VERSION 5.8 ;
BUSBITCHARS "[]" ;
DIVIDERCHAR "/" ;
UNITS
    DATABASE MICRONS 1000 ;
END UNITS

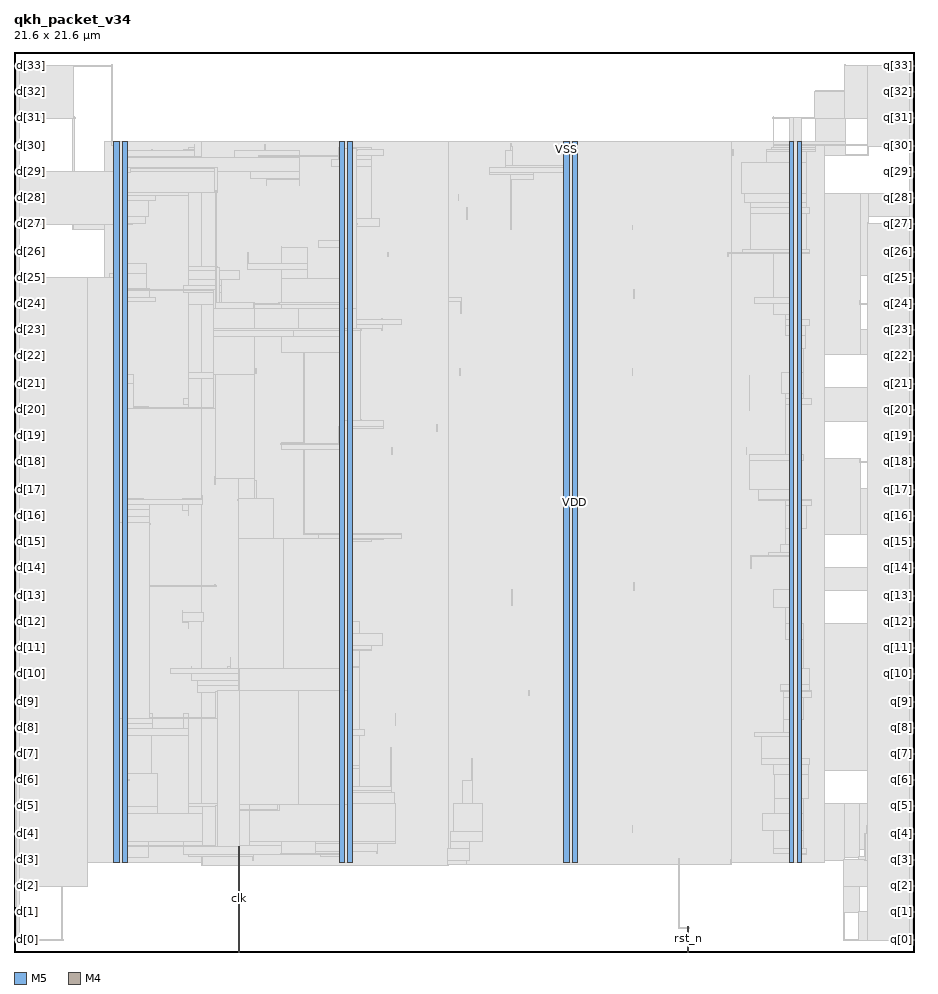
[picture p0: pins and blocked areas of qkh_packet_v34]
MACRO qkh_packet_v34
  FOREIGN qkh_packet_v34 0 0 ;
  CLASS BLOCK ;
  SIZE 21.6 BY 21.6 ;
  PIN clk
    DIRECTION INPUT ;
    USE SIGNAL ;
    PORT
      LAYER M5 ;
        RECT  5.376 0 5.4 0.084 ;
    END
    PORT
      LAYER M5 ;
        RECT  5.376 0.016 5.4 2.533 ;
    END
  END clk
  PIN d[0]
    DIRECTION INPUT ;
    USE SIGNAL ;
    PORT
      LAYER M4 ;
        RECT  0 0.288 0.084 0.312 ;
    END
  END d[0]
  PIN d[10]
    DIRECTION INPUT ;
    USE SIGNAL ;
    PORT
      LAYER M4 ;
        RECT  0 6.672 0.084 6.696 ;
    END
  END d[10]
  PIN d[11]
    DIRECTION INPUT ;
    USE SIGNAL ;
    PORT
      LAYER M4 ;
        RECT  0 7.296 0.084 7.32 ;
    END
  END d[11]
  PIN d[12]
    DIRECTION INPUT ;
    USE SIGNAL ;
    PORT
      LAYER M4 ;
        RECT  0 7.92 0.084 7.944 ;
    END
  END d[12]
  PIN d[13]
    DIRECTION INPUT ;
    USE SIGNAL ;
    PORT
      LAYER M4 ;
        RECT  0 8.544 0.084 8.568 ;
    END
  END d[13]
  PIN d[14]
    DIRECTION INPUT ;
    USE SIGNAL ;
    PORT
      LAYER M4 ;
        RECT  0 9.216 0.084 9.24 ;
    END
  END d[14]
  PIN d[15]
    DIRECTION INPUT ;
    USE SIGNAL ;
    PORT
      LAYER M4 ;
        RECT  0 9.84 0.084 9.864 ;
    END
  END d[15]
  PIN d[16]
    DIRECTION INPUT ;
    USE SIGNAL ;
    PORT
      LAYER M4 ;
        RECT  0 10.464 0.084 10.488 ;
    END
  END d[16]
  PIN d[17]
    DIRECTION INPUT ;
    USE SIGNAL ;
    PORT
      LAYER M4 ;
        RECT  0 11.088 0.084 11.112 ;
    END
  END d[17]
  PIN d[18]
    DIRECTION INPUT ;
    USE SIGNAL ;
    PORT
      LAYER M4 ;
        RECT  0 11.76 0.084 11.784 ;
    END
  END d[18]
  PIN d[19]
    DIRECTION INPUT ;
    USE SIGNAL ;
    PORT
      LAYER M4 ;
        RECT  0 12.384 0.084 12.408 ;
    END
  END d[19]
  PIN d[1]
    DIRECTION INPUT ;
    USE SIGNAL ;
    PORT
      LAYER M4 ;
        RECT  0 0.96 0.084 0.984 ;
    END
  END d[1]
  PIN d[20]
    DIRECTION INPUT ;
    USE SIGNAL ;
    PORT
      LAYER M4 ;
        RECT  0 13.008 0.084 13.032 ;
    END
  END d[20]
  PIN d[21]
    DIRECTION INPUT ;
    USE SIGNAL ;
    PORT
      LAYER M4 ;
        RECT  0 13.632 0.084 13.656 ;
    END
  END d[21]
  PIN d[22]
    DIRECTION INPUT ;
    USE SIGNAL ;
    PORT
      LAYER M4 ;
        RECT  0 14.304 0.084 14.328 ;
    END
  END d[22]
  PIN d[23]
    DIRECTION INPUT ;
    USE SIGNAL ;
    PORT
      LAYER M4 ;
        RECT  0 14.928 0.084 14.952 ;
    END
  END d[23]
  PIN d[24]
    DIRECTION INPUT ;
    USE SIGNAL ;
    PORT
      LAYER M4 ;
        RECT  0 15.552 0.084 15.576 ;
    END
  END d[24]
  PIN d[25]
    DIRECTION INPUT ;
    USE SIGNAL ;
    PORT
      LAYER M4 ;
        RECT  0 16.176 0.084 16.2 ;
    END
  END d[25]
  PIN d[26]
    DIRECTION INPUT ;
    USE SIGNAL ;
    PORT
      LAYER M4 ;
        RECT  0 16.8 0.084 16.824 ;
    END
  END d[26]
  PIN d[27]
    DIRECTION INPUT ;
    USE SIGNAL ;
    PORT
      LAYER M4 ;
        RECT  0 17.472 0.084 17.496 ;
    END
  END d[27]
  PIN d[28]
    DIRECTION INPUT ;
    USE SIGNAL ;
    PORT
      LAYER M4 ;
        RECT  0 18.096 0.084 18.12 ;
    END
  END d[28]
  PIN d[29]
    DIRECTION INPUT ;
    USE SIGNAL ;
    PORT
      LAYER M4 ;
        RECT  0 18.72 0.084 18.744 ;
    END
  END d[29]
  PIN d[2]
    DIRECTION INPUT ;
    USE SIGNAL ;
    PORT
      LAYER M4 ;
        RECT  0 1.584 0.084 1.608 ;
    END
  END d[2]
  PIN d[30]
    DIRECTION INPUT ;
    USE SIGNAL ;
    PORT
      LAYER M4 ;
        RECT  0 19.344 0.084 19.368 ;
    END
  END d[30]
  PIN d[31]
    DIRECTION INPUT ;
    USE SIGNAL ;
    PORT
      LAYER M4 ;
        RECT  0 20.016 0.084 20.04 ;
    END
  END d[31]
  PIN d[32]
    DIRECTION INPUT ;
    USE SIGNAL ;
    PORT
      LAYER M4 ;
        RECT  0 20.64 0.084 20.664 ;
    END
  END d[32]
  PIN d[33]
    DIRECTION INPUT ;
    USE SIGNAL ;
    PORT
      LAYER M4 ;
        RECT  0 21.264 0.084 21.288 ;
    END
  END d[33]
  PIN d[3]
    DIRECTION INPUT ;
    USE SIGNAL ;
    PORT
      LAYER M4 ;
        RECT  0 2.208 0.084 2.232 ;
    END
  END d[3]
  PIN d[4]
    DIRECTION INPUT ;
    USE SIGNAL ;
    PORT
      LAYER M4 ;
        RECT  0 2.832 0.084 2.856 ;
    END
  END d[4]
  PIN d[5]
    DIRECTION INPUT ;
    USE SIGNAL ;
    PORT
      LAYER M4 ;
        RECT  0 3.504 0.084 3.528 ;
    END
  END d[5]
  PIN d[6]
    DIRECTION INPUT ;
    USE SIGNAL ;
    PORT
      LAYER M4 ;
        RECT  0 4.128 0.084 4.152 ;
    END
  END d[6]
  PIN d[7]
    DIRECTION INPUT ;
    USE SIGNAL ;
    PORT
      LAYER M4 ;
        RECT  0 4.752 0.084 4.776 ;
    END
  END d[7]
  PIN d[8]
    DIRECTION INPUT ;
    USE SIGNAL ;
    PORT
      LAYER M4 ;
        RECT  0 5.376 0.084 5.4 ;
    END
  END d[8]
  PIN d[9]
    DIRECTION INPUT ;
    USE SIGNAL ;
    PORT
      LAYER M4 ;
        RECT  0 6 0.084 6.024 ;
    END
  END d[9]
  PIN q[0]
    DIRECTION OUTPUT ;
    USE SIGNAL ;
    PORT
      LAYER M4 ;
        RECT  21.516 0.288 21.6 0.312 ;
    END
  END q[0]
  PIN q[10]
    DIRECTION OUTPUT ;
    USE SIGNAL ;
    PORT
      LAYER M4 ;
        RECT  21.516 6.672 21.6 6.696 ;
    END
  END q[10]
  PIN q[11]
    DIRECTION OUTPUT ;
    USE SIGNAL ;
    PORT
      LAYER M4 ;
        RECT  21.516 7.296 21.6 7.32 ;
    END
  END q[11]
  PIN q[12]
    DIRECTION OUTPUT ;
    USE SIGNAL ;
    PORT
      LAYER M4 ;
        RECT  21.516 7.92 21.6 7.944 ;
    END
  END q[12]
  PIN q[13]
    DIRECTION OUTPUT ;
    USE SIGNAL ;
    PORT
      LAYER M4 ;
        RECT  21.516 8.544 21.6 8.568 ;
    END
  END q[13]
  PIN q[14]
    DIRECTION OUTPUT ;
    USE SIGNAL ;
    PORT
      LAYER M4 ;
        RECT  21.516 9.216 21.6 9.24 ;
    END
  END q[14]
  PIN q[15]
    DIRECTION OUTPUT ;
    USE SIGNAL ;
    PORT
      LAYER M4 ;
        RECT  21.516 9.84 21.6 9.864 ;
    END
  END q[15]
  PIN q[16]
    DIRECTION OUTPUT ;
    USE SIGNAL ;
    PORT
      LAYER M4 ;
        RECT  21.516 10.464 21.6 10.488 ;
    END
  END q[16]
  PIN q[17]
    DIRECTION OUTPUT ;
    USE SIGNAL ;
    PORT
      LAYER M4 ;
        RECT  21.516 11.088 21.6 11.112 ;
    END
  END q[17]
  PIN q[18]
    DIRECTION OUTPUT ;
    USE SIGNAL ;
    PORT
      LAYER M4 ;
        RECT  21.516 11.76 21.6 11.784 ;
    END
  END q[18]
  PIN q[19]
    DIRECTION OUTPUT ;
    USE SIGNAL ;
    PORT
      LAYER M4 ;
        RECT  21.516 12.384 21.6 12.408 ;
    END
  END q[19]
  PIN q[1]
    DIRECTION OUTPUT ;
    USE SIGNAL ;
    PORT
      LAYER M4 ;
        RECT  21.516 0.96 21.6 0.984 ;
    END
  END q[1]
  PIN q[20]
    DIRECTION OUTPUT ;
    USE SIGNAL ;
    PORT
      LAYER M4 ;
        RECT  21.516 13.008 21.6 13.032 ;
    END
  END q[20]
  PIN q[21]
    DIRECTION OUTPUT ;
    USE SIGNAL ;
    PORT
      LAYER M4 ;
        RECT  21.516 13.632 21.6 13.656 ;
    END
  END q[21]
  PIN q[22]
    DIRECTION OUTPUT ;
    USE SIGNAL ;
    PORT
      LAYER M4 ;
        RECT  21.516 14.304 21.6 14.328 ;
    END
  END q[22]
  PIN q[23]
    DIRECTION OUTPUT ;
    USE SIGNAL ;
    PORT
      LAYER M4 ;
        RECT  21.516 14.928 21.6 14.952 ;
    END
  END q[23]
  PIN q[24]
    DIRECTION OUTPUT ;
    USE SIGNAL ;
    PORT
      LAYER M4 ;
        RECT  21.516 15.552 21.6 15.576 ;
    END
  END q[24]
  PIN q[25]
    DIRECTION OUTPUT ;
    USE SIGNAL ;
    PORT
      LAYER M4 ;
        RECT  21.516 16.176 21.6 16.2 ;
    END
  END q[25]
  PIN q[26]
    DIRECTION OUTPUT ;
    USE SIGNAL ;
    PORT
      LAYER M4 ;
        RECT  21.516 16.8 21.6 16.824 ;
    END
  END q[26]
  PIN q[27]
    DIRECTION OUTPUT ;
    USE SIGNAL ;
    PORT
      LAYER M4 ;
        RECT  21.516 17.472 21.6 17.496 ;
    END
  END q[27]
  PIN q[28]
    DIRECTION OUTPUT ;
    USE SIGNAL ;
    PORT
      LAYER M4 ;
        RECT  21.516 18.096 21.6 18.12 ;
    END
  END q[28]
  PIN q[29]
    DIRECTION OUTPUT ;
    USE SIGNAL ;
    PORT
      LAYER M4 ;
        RECT  21.516 18.72 21.6 18.744 ;
    END
  END q[29]
  PIN q[2]
    DIRECTION OUTPUT ;
    USE SIGNAL ;
    PORT
      LAYER M4 ;
        RECT  21.516 1.584 21.6 1.608 ;
    END
  END q[2]
  PIN q[30]
    DIRECTION OUTPUT ;
    USE SIGNAL ;
    PORT
      LAYER M4 ;
        RECT  21.516 19.344 21.6 19.368 ;
    END
  END q[30]
  PIN q[31]
    DIRECTION OUTPUT ;
    USE SIGNAL ;
    PORT
      LAYER M4 ;
        RECT  21.516 20.016 21.6 20.04 ;
    END
  END q[31]
  PIN q[32]
    DIRECTION OUTPUT ;
    USE SIGNAL ;
    PORT
      LAYER M4 ;
        RECT  21.516 20.64 21.6 20.664 ;
    END
  END q[32]
  PIN q[33]
    DIRECTION OUTPUT ;
    USE SIGNAL ;
    PORT
      LAYER M4 ;
        RECT  21.516 21.264 21.6 21.288 ;
    END
  END q[33]
  PIN q[3]
    DIRECTION OUTPUT ;
    USE SIGNAL ;
    PORT
      LAYER M4 ;
        RECT  21.516 2.208 21.6 2.232 ;
    END
  END q[3]
  PIN q[4]
    DIRECTION OUTPUT ;
    USE SIGNAL ;
    PORT
      LAYER M4 ;
        RECT  21.516 2.832 21.6 2.856 ;
    END
  END q[4]
  PIN q[5]
    DIRECTION OUTPUT ;
    USE SIGNAL ;
    PORT
      LAYER M4 ;
        RECT  21.516 3.504 21.6 3.528 ;
    END
  END q[5]
  PIN q[6]
    DIRECTION OUTPUT ;
    USE SIGNAL ;
    PORT
      LAYER M4 ;
        RECT  21.516 4.128 21.6 4.152 ;
    END
  END q[6]
  PIN q[7]
    DIRECTION OUTPUT ;
    USE SIGNAL ;
    PORT
      LAYER M4 ;
        RECT  21.516 4.752 21.6 4.776 ;
    END
  END q[7]
  PIN q[8]
    DIRECTION OUTPUT ;
    USE SIGNAL ;
    PORT
      LAYER M4 ;
        RECT  21.516 5.376 21.6 5.4 ;
    END
  END q[8]
  PIN q[9]
    DIRECTION OUTPUT ;
    USE SIGNAL ;
    PORT
      LAYER M4 ;
        RECT  21.516 6 21.6 6.024 ;
    END
  END q[9]
  PIN rst_n
    DIRECTION INPUT ;
    USE SIGNAL ;
    PORT
      LAYER M5 ;
        RECT  16.176 0 16.2 0.084 ;
    END
    PORT
      LAYER M5 ;
        RECT  16.176 0.016 16.2 0.611 ;
    END
  END rst_n
  PIN VDD
    DIRECTION INOUT ;
    USE POWER ;
    PORT
      LAYER M5 ;
        RECT  18.792 2.151 18.912 19.449 ;
        RECT  13.392 2.151 13.512 19.449 ;
        RECT  7.992 2.151 8.112 19.449 ;
        RECT  2.592 2.151 2.712 19.449 ;
    END
  END VDD
  PIN VSS
    DIRECTION INOUT ;
    USE GROUND ;
    PORT
      LAYER M5 ;
        RECT  18.6 2.137 18.72 19.463 ;
        RECT  13.2 2.137 13.32 19.463 ;
        RECT  7.8 2.137 7.92 19.463 ;
        RECT  2.4 2.137 2.52 19.463 ;
    END
  END VSS
  # OT_OBS_CLOSED layer=M5 d_um=1.536 added=7
  OBS
    LAYER RVTN ;
     RECT  2.16 2.16 19.44 2.295 ;
     RECT  2.16 2.565 19.44 2.835 ;
     RECT  2.16 3.105 19.44 3.375 ;
     RECT  2.16 3.645 19.44 3.915 ;
     RECT  2.16 4.185 19.44 4.455 ;
     RECT  2.16 4.725 19.44 4.995 ;
     RECT  2.16 5.265 19.44 5.535 ;
     RECT  2.16 5.805 19.44 6.075 ;
     RECT  2.16 6.345 19.44 6.615 ;
     RECT  2.16 6.885 19.44 7.155 ;
     RECT  2.16 7.425 19.44 7.695 ;
     RECT  2.16 7.965 19.44 8.235 ;
     RECT  2.16 8.505 19.44 8.775 ;
     RECT  2.16 9.045 19.44 9.315 ;
     RECT  2.16 9.585 19.44 9.855 ;
     RECT  2.16 10.125 19.44 10.395 ;
     RECT  2.16 10.665 19.44 10.935 ;
     RECT  2.16 11.205 19.44 11.475 ;
     RECT  2.16 11.745 19.44 12.015 ;
     RECT  2.16 12.285 19.44 12.555 ;
     RECT  2.16 12.825 19.44 13.095 ;
     RECT  2.16 13.365 19.44 13.635 ;
     RECT  2.16 13.905 19.44 14.175 ;
     RECT  2.16 14.445 19.44 14.715 ;
     RECT  2.16 14.985 19.44 15.255 ;
     RECT  2.16 15.525 19.44 15.795 ;
     RECT  2.16 16.065 19.44 16.335 ;
     RECT  2.16 16.605 19.44 16.875 ;
     RECT  2.16 17.145 19.44 17.415 ;
     RECT  2.16 17.685 19.44 17.955 ;
     RECT  2.16 18.225 19.44 18.495 ;
     RECT  2.16 18.765 19.44 19.035 ;
     RECT  2.16 19.305 19.44 19.44 ;
    LAYER RVTP ;
     RECT  2.16 2.295 19.44 2.565 ;
     RECT  2.16 2.835 19.44 3.105 ;
     RECT  2.16 3.375 19.44 3.645 ;
     RECT  2.16 3.915 19.44 4.185 ;
     RECT  2.16 4.455 19.44 4.725 ;
     RECT  2.16 4.995 19.44 5.265 ;
     RECT  2.16 5.535 19.44 5.805 ;
     RECT  2.16 6.075 19.44 6.345 ;
     RECT  2.16 6.615 19.44 6.885 ;
     RECT  2.16 7.155 19.44 7.425 ;
     RECT  2.16 7.695 19.44 7.965 ;
     RECT  2.16 8.235 19.44 8.505 ;
     RECT  2.16 8.775 19.44 9.045 ;
     RECT  2.16 9.315 19.44 9.585 ;
     RECT  2.16 9.855 19.44 10.125 ;
     RECT  2.16 10.395 19.44 10.665 ;
     RECT  2.16 10.935 19.44 11.205 ;
     RECT  2.16 11.475 19.44 11.745 ;
     RECT  2.16 12.015 19.44 12.285 ;
     RECT  2.16 12.555 19.44 12.825 ;
     RECT  2.16 13.095 19.44 13.365 ;
     RECT  2.16 13.635 19.44 13.905 ;
     RECT  2.16 14.175 19.44 14.445 ;
     RECT  2.16 14.715 19.44 14.985 ;
     RECT  2.16 15.255 19.44 15.525 ;
     RECT  2.16 15.795 19.44 16.065 ;
     RECT  2.16 16.335 19.44 16.605 ;
     RECT  2.16 16.875 19.44 17.145 ;
     RECT  2.16 17.415 19.44 17.685 ;
     RECT  2.16 17.955 19.44 18.225 ;
     RECT  2.16 18.495 19.44 18.765 ;
     RECT  2.16 19.035 19.44 19.305 ;
    LAYER M1 ;
     RECT  2.16 2.151 19.44 19.449 ;
    LAYER M2 ;
     RECT  0.031 4.122 1.147 4.14 ;
     RECT  0.103 17.658 1.399 17.676 ;
     RECT  1.723 2.232 2.16 2.25 ;
     RECT  1.147 3.582 2.16 4.14 ;
     RECT  0.103 15.84 2.16 15.858 ;
     RECT  1.399 17.352 2.16 17.676 ;
     RECT  1.435 18.702 2.16 18.72 ;
     RECT  2.16 2.151 4.495 19.449 ;
     RECT  4.495 2.07 10.427 19.449 ;
     RECT  10.427 2.106 17.231 19.449 ;
     RECT  17.231 2.151 19.44 19.449 ;
     RECT  19.44 2.196 19.931 3.564 ;
     RECT  19.44 19.116 19.967 19.368 ;
     RECT  19.931 2.268 20.291 3.564 ;
     RECT  19.44 10.026 20.327 11.844 ;
     RECT  19.44 14.346 20.327 18.216 ;
     RECT  20.291 2.466 20.507 3.564 ;
     RECT  19.44 4.356 20.507 7.884 ;
     RECT  19.44 8.676 20.507 9.234 ;
     RECT  20.327 10.026 20.507 11.124 ;
     RECT  19.44 12.726 20.507 13.554 ;
     RECT  20.327 14.346 20.507 14.94 ;
     RECT  20.327 16.236 20.507 18.216 ;
     RECT  19.967 19.116 20.507 19.134 ;
     RECT  20.507 17.658 21.515 18.216 ;
    LAYER M3 ;
     RECT  19.908 0.283 19.926 0.955 ;
     RECT  0.108 0.955 0.126 1.099 ;
     RECT  0.036 1.099 0.126 1.133 ;
     RECT  1.152 0.283 1.17 1.579 ;
     RECT  19.908 0.955 20.286 1.579 ;
     RECT  10.404 2.065 10.422 2.101 ;
     RECT  1.152 1.579 1.746 2.143 ;
     RECT  10.404 2.101 10.854 2.191 ;
     RECT  17.208 2.101 17.226 2.219 ;
     RECT  19.908 1.579 20.502 2.219 ;
     RECT  1.152 2.143 2.505 2.255 ;
     RECT  15.948 0.571 15.966 2.255 ;
     RECT  2.304 2.255 2.505 2.263 ;
     RECT  18.615 2.143 18.705 2.263 ;
     RECT  20.268 2.219 20.502 2.291 ;
     RECT  4.5 2.065 4.518 2.299 ;
     RECT  5.724 2.191 5.742 2.299 ;
     RECT  7.815 2.143 7.905 2.299 ;
     RECT  4.176 2.299 5.742 2.335 ;
     RECT  7.344 2.299 7.905 2.335 ;
     RECT  18.615 2.263 18.774 2.335 ;
     RECT  18.615 2.335 19.026 2.371 ;
     RECT  7.236 2.335 7.905 2.413 ;
     RECT  8.712 2.371 8.73 2.413 ;
     RECT  13.215 2.143 13.305 2.413 ;
     RECT  10.404 2.191 10.926 2.489 ;
     RECT  18.216 2.371 19.026 2.489 ;
     RECT  2.304 2.263 3.222 2.525 ;
     RECT  4.068 2.335 6.426 2.561 ;
     RECT  7.236 2.413 8.73 2.605 ;
     RECT  2.415 2.525 3.222 2.641 ;
     RECT  4.068 2.561 4.518 2.641 ;
     RECT  5.652 2.561 6.426 2.641 ;
     RECT  7.236 2.605 9.162 2.641 ;
     RECT  10.476 2.489 10.926 2.641 ;
     RECT  20.412 2.291 20.502 2.842 ;
     RECT  10.476 2.641 11.25 2.903 ;
     RECT  18.216 2.489 18.954 2.911 ;
     RECT  14.832 2.875 14.85 3.029 ;
     RECT  20.448 2.842 20.502 3.029 ;
     RECT  2.415 2.641 4.518 3.335 ;
     RECT  17.964 2.911 18.954 3.335 ;
     RECT  2.415 3.335 3.438 3.499 ;
     RECT  4.176 3.335 4.518 3.499 ;
     RECT  4.176 3.499 4.878 3.569 ;
     RECT  5.652 2.641 9.162 3.569 ;
     RECT  10.548 2.903 11.25 3.569 ;
     RECT  1.152 2.255 1.17 3.605 ;
     RECT  18.252 3.335 18.954 3.685 ;
     RECT  5.652 3.569 9.126 3.839 ;
     RECT  5.652 3.839 9.054 3.875 ;
     RECT  5.796 3.875 6.354 3.947 ;
     RECT  7.272 3.875 9.054 3.983 ;
     RECT  10.764 3.569 10.998 4.109 ;
     RECT  0.036 1.133 0.054 4.145 ;
     RECT  6.336 3.947 6.354 4.145 ;
     RECT  18.252 3.685 19.062 4.261 ;
     RECT  2.304 3.499 3.438 4.289 ;
     RECT  7.272 3.983 8.298 4.415 ;
     RECT  7.308 4.415 8.298 4.487 ;
     RECT  18.216 4.261 19.062 4.495 ;
     RECT  10.98 4.109 10.998 4.649 ;
     RECT  17.928 4.495 19.098 4.649 ;
     RECT  9.036 3.983 9.054 4.919 ;
     RECT  17.928 4.649 18.897 5.161 ;
     RECT  2.304 4.289 3.294 5.197 ;
     RECT  4.176 3.569 4.194 5.197 ;
     RECT  7.38 4.487 8.298 5.197 ;
     RECT  17.784 5.161 18.897 5.261 ;
     RECT  7.38 5.197 8.406 5.333 ;
     RECT  2.304 5.197 4.194 5.369 ;
     RECT  2.304 5.369 3.33 5.495 ;
     RECT  0.108 5.371 0.126 5.501 ;
     RECT  18.468 5.261 18.897 5.575 ;
     RECT  2.34 5.495 3.33 5.729 ;
     RECT  4.068 5.369 4.194 5.729 ;
     RECT  9.144 5.431 9.162 5.729 ;
     RECT  18.468 5.575 18.954 6.115 ;
     RECT  5.112 6.151 5.526 6.235 ;
     RECT  18.468 6.115 19.134 6.241 ;
     RECT  12.348 6.151 12.366 6.269 ;
     RECT  18.396 6.241 19.134 6.269 ;
     RECT  2.34 5.729 3.222 6.305 ;
     RECT  4.392 6.235 5.526 6.385 ;
     RECT  6.48 6.235 6.498 6.385 ;
     RECT  18.396 6.269 19.098 6.413 ;
     RECT  4.392 6.385 6.498 6.511 ;
     RECT  2.34 6.305 2.697 6.667 ;
     RECT  4.248 6.511 6.498 6.691 ;
     RECT  3.744 6.691 6.57 6.809 ;
     RECT  18.615 6.413 19.098 6.809 ;
     RECT  6.192 6.809 6.57 6.817 ;
     RECT  7.38 5.333 8.298 6.817 ;
     RECT  4.248 6.809 4.266 6.845 ;
     RECT  5.112 6.809 5.202 6.845 ;
     RECT  6.192 6.817 8.298 6.845 ;
     RECT  5.184 6.845 5.202 7.079 ;
     RECT  7.2 6.845 8.298 7.231 ;
     RECT  7.2 7.231 8.586 7.259 ;
     RECT  7.815 7.259 8.586 7.357 ;
     RECT  18.615 6.809 18.954 7.501 ;
     RECT  7.815 7.357 8.838 7.655 ;
     RECT  18.504 7.501 18.954 7.889 ;
     RECT  4.176 7.771 4.194 7.897 ;
     RECT  7.815 7.655 8.298 7.925 ;
     RECT  2.304 6.667 2.697 7.933 ;
     RECT  4.032 7.897 4.194 7.933 ;
     RECT  2.304 7.933 3.222 7.997 ;
     RECT  4.032 7.933 4.554 8.159 ;
     RECT  4.032 8.159 4.05 8.195 ;
     RECT  18.504 7.889 18.897 8.275 ;
     RECT  11.952 8.311 11.97 8.699 ;
     RECT  18.216 8.275 18.897 8.699 ;
     RECT  4.824 8.773 4.842 8.813 ;
     RECT  5.724 7.771 5.742 8.815 ;
     RECT  14.868 8.671 14.886 8.879 ;
     RECT  5.688 8.815 5.742 8.969 ;
     RECT  7.815 7.925 8.097 9.121 ;
     RECT  5.724 8.969 5.742 9.149 ;
     RECT  2.304 7.997 2.697 9.275 ;
     RECT  7.344 9.121 8.097 9.355 ;
     RECT  6.408 9.307 6.426 9.383 ;
     RECT  17.676 9.211 17.694 9.481 ;
     RECT  18.615 8.699 18.897 9.481 ;
     RECT  17.676 9.481 18.897 9.509 ;
     RECT  18.108 9.509 18.897 9.581 ;
     RECT  18.396 9.581 18.897 9.779 ;
     RECT  2.415 9.275 2.697 9.787 ;
     RECT  7.308 9.355 8.097 9.859 ;
     RECT  7.308 9.859 8.586 9.895 ;
     RECT  7.308 9.895 8.874 9.931 ;
     RECT  7.308 9.931 9.306 10.021 ;
     RECT  6.948 10.021 9.306 10.049 ;
     RECT  18.504 9.779 18.897 10.165 ;
     RECT  2.415 9.787 2.826 10.267 ;
     RECT  2.415 10.267 3.258 10.459 ;
     RECT  4.176 10.471 4.194 10.597 ;
     RECT  2.304 10.459 3.258 10.625 ;
     RECT  18.504 10.165 19.026 10.705 ;
     RECT  2.34 10.625 3.258 10.741 ;
     RECT  4.032 10.597 4.194 10.741 ;
     RECT  5.796 10.471 5.814 10.831 ;
     RECT  18.504 10.705 19.134 10.831 ;
     RECT  5.796 10.831 5.922 10.843 ;
     RECT  2.34 10.741 4.518 10.859 ;
     RECT  17.856 10.831 19.134 10.859 ;
     RECT  5.652 10.843 5.922 10.877 ;
     RECT  2.34 10.859 3.114 10.895 ;
     RECT  4.032 10.859 4.518 10.895 ;
     RECT  4.5 10.895 4.518 10.967 ;
     RECT  17.856 10.859 18.897 11.101 ;
     RECT  20.484 3.029 20.502 11.129 ;
     RECT  5.652 10.877 5.814 11.309 ;
     RECT  4.824 11.209 4.842 11.405 ;
     RECT  5.652 11.309 5.67 11.435 ;
     RECT  2.34 10.895 2.697 11.755 ;
     RECT  17.64 11.101 18.897 11.785 ;
     RECT  20.304 11.755 20.322 11.849 ;
     RECT  17.64 11.785 18.954 11.939 ;
     RECT  6.948 10.049 6.966 12.055 ;
     RECT  7.815 10.049 8.097 12.055 ;
     RECT  9.072 11.947 9.09 12.119 ;
     RECT  17.568 11.947 17.586 12.119 ;
     RECT  6.408 12.055 8.097 12.209 ;
     RECT  6.408 12.209 6.966 12.221 ;
     RECT  7.776 12.209 8.097 12.559 ;
     RECT  7.776 12.559 8.874 12.623 ;
     RECT  10.152 12.487 10.17 12.659 ;
     RECT  7.815 12.623 8.874 12.749 ;
     RECT  7.815 12.749 8.154 12.797 ;
     RECT  2.304 11.755 2.697 13.051 ;
     RECT  2.304 13.051 3.222 13.055 ;
     RECT  2.415 13.055 3.222 13.091 ;
     RECT  4.176 13.099 4.194 13.135 ;
     RECT  18.504 11.939 18.897 13.135 ;
     RECT  4.068 13.135 4.194 13.289 ;
     RECT  18.504 13.135 19.134 13.289 ;
     RECT  18.504 13.289 18.954 13.405 ;
     RECT  4.176 13.289 4.194 13.771 ;
     RECT  17.64 12.991 17.658 13.829 ;
     RECT  2.415 13.091 2.862 13.865 ;
     RECT  5.688 13.639 5.706 13.865 ;
     RECT  4.176 13.771 4.878 13.901 ;
     RECT  18.432 13.405 18.954 13.901 ;
     RECT  5.796 13.873 5.814 14.009 ;
     RECT  10.692 13.837 10.71 14.009 ;
     RECT  14.832 13.837 14.85 14.009 ;
     RECT  2.415 13.865 2.697 14.299 ;
     RECT  6.948 12.221 6.966 14.377 ;
     RECT  7.815 12.797 8.097 14.377 ;
     RECT  18.615 13.901 18.954 14.485 ;
     RECT  18.615 14.485 18.99 14.791 ;
     RECT  6.408 14.377 8.097 14.953 ;
     RECT  8.82 14.917 8.838 14.953 ;
     RECT  20.484 12.379 20.502 14.957 ;
     RECT  18.504 14.791 18.99 15.025 ;
     RECT  6.408 14.953 8.838 15.061 ;
     RECT  6.408 15.061 9.306 15.179 ;
     RECT  18.504 15.025 19.098 15.179 ;
     RECT  8.82 15.179 8.838 15.215 ;
     RECT  18.504 15.179 18.897 15.295 ;
     RECT  6.408 15.179 8.097 15.529 ;
     RECT  4.176 13.901 4.194 15.547 ;
     RECT  4.968 15.398 4.986 15.547 ;
     RECT  18.216 15.295 18.897 15.565 ;
     RECT  6.336 15.529 8.097 15.581 ;
     RECT  2.304 14.299 2.697 15.601 ;
     RECT  10.728 15.331 10.746 15.601 ;
     RECT  20.304 15.547 20.322 15.629 ;
     RECT  2.304 15.601 3.402 15.719 ;
     RECT  10.44 15.601 10.746 15.719 ;
     RECT  17.784 15.565 18.897 15.719 ;
     RECT  4.176 15.547 4.986 15.835 ;
     RECT  14.868 15.691 14.886 15.899 ;
     RECT  2.304 15.719 3.258 15.917 ;
     RECT  4.068 15.835 4.986 15.989 ;
     RECT  4.176 15.989 4.986 16.141 ;
     RECT  6.408 15.581 8.097 16.169 ;
     RECT  2.304 15.917 3.186 16.295 ;
     RECT  4.176 16.141 5.418 16.367 ;
     RECT  6.408 16.169 7.038 16.375 ;
     RECT  4.176 16.367 4.878 16.445 ;
     RECT  2.415 16.295 3.186 16.529 ;
     RECT  5.616 16.375 7.038 16.529 ;
     RECT  17.136 16.681 17.154 16.771 ;
     RECT  18.216 15.719 18.897 16.771 ;
     RECT  5.616 16.529 5.634 16.799 ;
     RECT  8.964 16.681 8.982 16.799 ;
     RECT  17.136 16.771 19.098 16.799 ;
     RECT  0.108 15.835 0.126 16.829 ;
     RECT  17.496 16.799 19.098 16.871 ;
     RECT  6.408 16.529 7.038 16.907 ;
     RECT  7.815 16.169 8.097 16.915 ;
     RECT  6.408 16.907 6.426 16.943 ;
     RECT  7.308 16.915 8.097 17.069 ;
     RECT  7.815 17.069 8.097 17.419 ;
     RECT  14.832 17.347 14.85 17.447 ;
     RECT  2.415 16.529 2.697 17.455 ;
     RECT  2.415 17.455 2.826 17.491 ;
     RECT  20.484 16.171 20.502 17.519 ;
     RECT  7.815 17.419 8.766 17.609 ;
     RECT  2.415 17.491 3.15 17.653 ;
     RECT  17.676 16.871 19.026 17.725 ;
     RECT  10.872 17.581 10.89 17.879 ;
     RECT  17.676 17.725 19.098 17.879 ;
     RECT  17.676 17.879 19.026 17.995 ;
     RECT  2.415 17.653 3.222 18.031 ;
     RECT  2.415 18.031 3.402 18.157 ;
     RECT  4.176 16.445 4.194 18.157 ;
     RECT  10.656 18.031 10.674 18.185 ;
     RECT  17.532 17.995 19.026 18.193 ;
     RECT  2.415 18.157 4.194 18.235 ;
     RECT  6.048 18.391 6.066 18.535 ;
     RECT  6.84 18.391 6.858 18.535 ;
     RECT  11.916 17.347 11.934 18.535 ;
     RECT  6.048 18.535 6.858 18.571 ;
     RECT  11.916 18.535 12.474 18.661 ;
     RECT  1.404 17.347 1.422 18.697 ;
     RECT  11.412 18.661 12.474 18.697 ;
     RECT  13.215 2.413 13.497 18.697 ;
     RECT  2.415 18.235 4.878 18.733 ;
     RECT  5.688 18.571 6.858 18.733 ;
     RECT  21.492 17.653 21.51 18.749 ;
     RECT  11.412 18.697 13.497 18.833 ;
     RECT  7.815 17.609 8.586 18.841 ;
     RECT  11.808 18.833 13.497 18.869 ;
     RECT  17.46 18.193 19.026 18.959 ;
     RECT  7.632 18.841 8.586 19.031 ;
     RECT  2.415 18.733 6.858 19.067 ;
     RECT  2.415 19.067 4.482 19.103 ;
     RECT  7.776 19.031 8.586 19.111 ;
     RECT  13.215 18.869 13.497 19.187 ;
     RECT  18.072 18.959 19.026 19.201 ;
     RECT  2.415 19.103 4.338 19.229 ;
     RECT  5.292 19.067 6.858 19.229 ;
     RECT  11.808 18.869 11.97 19.229 ;
     RECT  3.312 19.229 3.33 19.265 ;
     RECT  4.068 19.229 4.338 19.265 ;
     RECT  7.776 19.111 8.874 19.265 ;
     RECT  17.244 19.111 17.262 19.265 ;
     RECT  18.072 19.201 19.242 19.265 ;
     RECT  4.176 19.265 4.338 19.301 ;
     RECT  7.776 19.265 8.586 19.301 ;
     RECT  18.18 19.265 19.242 19.301 ;
     RECT  11.916 19.229 11.97 19.337 ;
     RECT  2.415 19.229 2.505 19.345 ;
     RECT  18.216 19.301 19.242 19.345 ;
     RECT  20.484 19.111 20.502 19.345 ;
     RECT  0.108 17.653 0.126 19.373 ;
     RECT  4.32 19.301 4.338 19.373 ;
     RECT  6.012 19.229 6.03 19.373 ;
     RECT  18.216 19.345 20.502 19.373 ;
     RECT  11.916 19.337 11.934 19.409 ;
     RECT  2.34 19.345 2.505 19.457 ;
     RECT  7.815 19.301 7.905 19.457 ;
     RECT  13.215 19.187 13.305 19.457 ;
     RECT  18.216 19.373 19.962 19.457 ;
     RECT  1.404 18.697 1.458 20.045 ;
     RECT  18.216 19.457 18.234 20.045 ;
     RECT  1.404 20.045 1.422 20.669 ;
     RECT  19.224 19.457 19.962 20.669 ;
     RECT  2.34 19.457 2.358 21.293 ;
     RECT  19.944 20.669 19.962 21.293 ;
    LAYER M4 ;
     RECT  0.025 1.104 0.06 1.128 ;
     RECT  0.06 0.288 0.137 21.288 ;
     RECT  0.137 0.288 1.181 0.312 ;
     RECT  0.137 20.016 1.433 21.288 ;
     RECT  1.433 20.016 1.469 20.04 ;
     RECT  0.137 1.584 1.757 16.2 ;
     RECT  1.433 21.264 2.369 21.288 ;
     RECT  1.757 2.148 2.408 16.2 ;
     RECT  0.137 17.472 2.408 18.744 ;
     RECT  2.408 2.148 2.512 19.452 ;
     RECT  2.512 2.418 2.704 19.182 ;
     RECT  2.704 4.128 2.765 4.152 ;
     RECT  2.704 18.72 2.801 18.84 ;
     RECT  2.704 9.84 2.837 10.296 ;
     RECT  2.704 17.472 2.837 17.496 ;
     RECT  2.704 13.056 2.873 13.656 ;
     RECT  2.704 5.616 3.233 6.024 ;
     RECT  2.704 7.968 3.251 8.808 ;
     RECT  2.837 10.272 3.269 10.296 ;
     RECT  2.873 13.056 4.789 13.08 ;
     RECT  2.704 15.888 4.789 15.912 ;
     RECT  2.801 18.816 4.805 18.84 ;
     RECT  4.789 15.408 4.837 15.912 ;
     RECT  2.704 2.544 4.844 2.568 ;
     RECT  3.233 5.616 4.844 5.64 ;
     RECT  3.251 8.784 4.853 8.808 ;
     RECT  4.789 13.056 4.883 13.896 ;
     RECT  4.883 13.776 4.889 13.896 ;
     RECT  4.805 18.24 4.889 18.84 ;
     RECT  4.813 11.376 4.897 11.4 ;
     RECT  4.889 13.776 4.924 13.8 ;
     RECT  4.837 15.408 4.924 16.44 ;
     RECT  4.844 2.544 4.931 3.528 ;
     RECT  4.844 5.616 4.931 6.264 ;
     RECT  4.924 15.408 4.997 15.576 ;
     RECT  5.365 10.848 6.227 10.872 ;
     RECT  4.931 3.408 6.325 3.432 ;
     RECT  6.325 3.408 6.365 3.576 ;
     RECT  4.997 15.552 6.365 15.576 ;
     RECT  6.181 6.816 6.421 6.84 ;
     RECT  6.38 9.312 6.421 9.336 ;
     RECT  6.421 9.312 6.467 9.912 ;
     RECT  6.421 6.816 6.469 7.416 ;
     RECT  6.469 6.24 6.509 7.416 ;
     RECT  6.397 14.784 6.707 15.432 ;
     RECT  6.509 6.24 6.805 6.264 ;
     RECT  6.397 2.352 7.808 2.376 ;
     RECT  6.365 3.552 7.808 3.576 ;
     RECT  6.805 5.664 7.808 6.264 ;
     RECT  6.509 7.392 7.808 7.416 ;
     RECT  6.467 9.888 7.808 9.912 ;
     RECT  6.397 12.192 7.808 12.216 ;
     RECT  6.707 14.928 7.808 15.432 ;
     RECT  5.857 19.104 7.808 19.128 ;
     RECT  7.808 2.148 7.912 19.452 ;
     RECT  7.912 2.418 8.104 19.272 ;
     RECT  8.104 17.472 8.243 17.496 ;
     RECT  8.104 19.248 8.243 19.272 ;
     RECT  8.104 12.768 8.339 12.792 ;
     RECT  8.104 14.928 8.339 14.952 ;
     RECT  13.208 2.148 13.312 19.452 ;
     RECT  13.312 2.418 13.504 19.182 ;
     RECT  15.937 0.576 16.211 0.6 ;
     RECT  18.205 20.016 18.608 20.04 ;
     RECT  18.608 2.148 18.712 20.04 ;
     RECT  18.712 2.418 18.904 20.04 ;
     RECT  18.904 20.016 19.213 20.04 ;
     RECT  19.213 20.016 19.933 20.664 ;
     RECT  19.897 0.288 20.257 0.312 ;
     RECT  20.401 2.208 20.437 2.232 ;
     RECT  20.257 0.288 20.473 0.984 ;
     RECT  20.437 2.208 20.473 2.856 ;
     RECT  20.293 11.76 20.473 11.784 ;
     RECT  20.293 15.552 20.473 15.576 ;
     RECT  19.933 20.016 20.473 21.288 ;
     RECT  20.473 0.288 21.481 17.496 ;
     RECT  20.473 19.344 21.481 21.288 ;
     RECT  21.481 0.288 21.564 21.288 ;
    LAYER M5 ;
     RECT  2.4 2.137 2.52 2.151 ;
     RECT  7.8 2.137 7.92 2.151 ;
     RECT  13.2 2.137 13.32 2.151 ;
     RECT  18.6 2.137 18.72 2.151 ;
     RECT  7.8 2.151 8.112 3.541 ;
     RECT  2.4 2.151 2.712 5.605 ;
     RECT  4.896 2.533 5.4 6.275 ;
     RECT  6.816 3.541 8.112 6.275 ;
     RECT  5.376 6.275 5.4 6.805 ;
     RECT  5.376 6.805 6.456 9.923 ;
     RECT  2.4 5.605 3.24 10.307 ;
     RECT  5.376 9.923 6.216 10.883 ;
     RECT  5.376 10.883 5.784 11.365 ;
     RECT  7.8 6.275 8.112 12.757 ;
     RECT  4.848 11.365 5.784 13.861 ;
     RECT  4.8 13.861 5.784 14.773 ;
     RECT  4.8 14.773 6.696 14.917 ;
     RECT  7.8 12.757 8.328 14.917 ;
     RECT  4.8 14.917 8.328 14.963 ;
     RECT  4.8 14.963 5.784 15.443 ;
     RECT  6.816 14.963 8.232 15.443 ;
     RECT  5.76 15.443 5.784 15.587 ;
     RECT  4.848 16.405 4.872 18.275 ;
     RECT  7.8 15.443 8.232 19.283 ;
     RECT  2.4 10.307 2.712 19.449 ;
     RECT  7.8 19.283 8.112 19.449 ;
     RECT  13.2 2.151 13.512 19.449 ;
     RECT  18.6 2.151 18.912 19.449 ;
     RECT  2.4 19.449 2.52 19.463 ;
     RECT  7.8 19.449 7.92 19.463 ;
     RECT  13.2 19.449 13.32 19.463 ;
     RECT  18.6 19.449 18.72 19.463 ;
     RECT  5.4 3.541 6.816 6.275 ;
     RECT  5.4 6.275 7.8 6.805 ;
     RECT  6.456 6.805 7.8 9.923 ;
     RECT  6.696 14.773 7.8 14.917 ;
     RECT  5.784 14.963 6.816 15.443 ;
     RECT  4.848 15.443 5.76 15.587 ;
     RECT  4.848 15.587 4.872 16.405 ;
  END
END qkh_packet_v34
END LIBRARY
